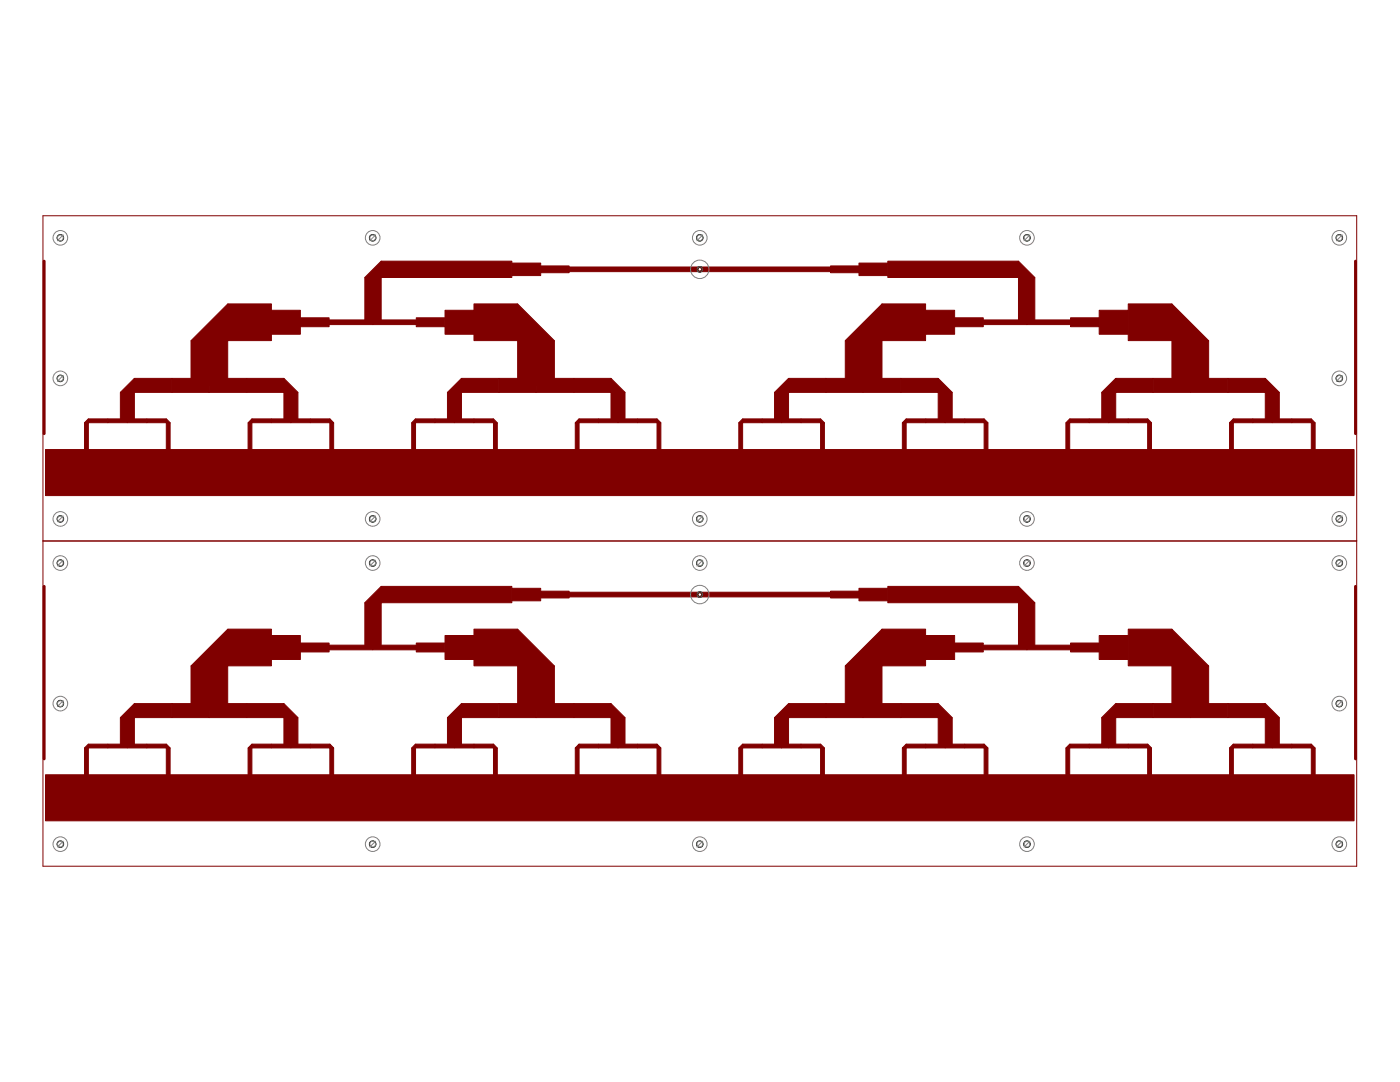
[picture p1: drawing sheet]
<svg xmlns="http://www.w3.org/2000/svg" width="279mm" height="216mm" viewBox="0 0 279 216" stroke-linecap="round" stroke-linejoin="round" font-family="sans-serif">
<circle cx="139.7" cy="118.6" r=".55" fill="#008000" stroke="#008000" stroke-width=".2"/>
<circle cx="139.7" cy="118.6" r=".36" fill="#fff" stroke="#000" stroke-width=".2"/>
<circle cx="139.7" cy="53.7" r=".55" fill="#008000" stroke="#008000" stroke-width=".2"/>
<circle cx="139.7" cy="53.7" r=".36" fill="#fff" stroke="#000" stroke-width=".2"/>
<g fill="#800000" stroke="#800000" stroke-width=".2">
<path d="M113.6 118.2h26.1v.9h-26.1z"/>
<path d="M139.7 118.2h26v.9h-26z"/>
<path d="M107.9 118h5.7v1.3h-5.7z"/>
<path d="M165.8 118h5.6v1.3h-5.6z"/>
<path d="M102.1 117.4h5.8v2.5h-5.8z"/>
<path d="M171.4 117.4h5.8v2.5h-5.8z"/>
<path d="M76.1 117h26v3.3h-26z"/>
<path d="M177.2 117h26.1v3.3h-26.1z"/>
<path d="M72.8 120.3l3.3-3.3 1.6 1.6-3.3 3.3z"/>
<path d="M203.3 117l3.2 3.3-1.6 1.6-3.3-3.3z"/>
<path d="M72.8 120.3h3.3v8.9h-3.3z"/>
<path d="M203.3 120.3h3.2v8.9h-3.2z"/>
<path d="M65.7 128.7h8.7v1h-8.7z"/>
<path d="M74.4 128.7h8.7v1h-8.7z"/>
<path d="M60 128.3h5.7v1.8h-5.7z"/>
<path d="M83.1 128.3h5.7v1.8h-5.7z"/>
<path d="M54.1 126.8h5.8v4.8h-5.8z"/>
<path d="M88.8 126.8h5.8v4.8h-5.8z"/>
<path d="M45.4 125.5h8.8v7.4h-8.8z"/>
<path d="M94.6 125.5h8.7v7.4h-8.7z"/>
<path d="M38.1 132.9l7.3-7.3 3.7 3.6-7.3 7.3z"/>
<path d="M230.2 129.2l3.7-3.6 7.3 7.3-3.7 3.6z"/>
<path d="M38.1 132.9h7.3v8.9h-7.3z"/>
<path d="M103.3 132.9h7.3v8.9h-7.3z"/>
<path d="M196.2 128.7h8.8v1h-8.8z"/>
<path d="M204.9 128.7h8.8v1h-8.8z"/>
<path d="M190.5 128.3h5.7v1.8h-5.7z"/>
<path d="M213.7 128.3h5.7v1.8h-5.7z"/>
<path d="M184.7 126.8h5.8v4.8h-5.8z"/>
<path d="M219.4 126.8h5.8v4.8h-5.8z"/>
<path d="M176 125.5h8.7v7.4h-8.7z"/>
<path d="M225.2 125.5h8.7v7.4h-8.7z"/>
<path d="M168.7 132.9l7.3-7.3 3.7 3.6-7.3 7.3z"/>
<path d="M99.7 129.2l3.6-3.6 7.3 7.3-3.6 3.6z"/>
<path d="M168.7 132.9h7.3v8.9h-7.3z"/>
<path d="M233.9 132.9h7.3v8.9h-7.3z"/>
<path d="M34.3 140.4h7.4v2.8h-7.4z"/>
<path d="M41.7 140.4h7.5v2.8h-7.5z"/>
<path d="M26.8 140.4h7.5v2.8h-7.5z"/>
<path d="M49.2 140.4h7.5v2.8h-7.5z"/>
<path d="M24 143.2l2.8-2.8 1.4 1.4-2.8 2.8z"/>
<path d="M251.1 141.8l1.4-1.4 2.8 2.8-1.4 1.4z"/>
<path d="M24 143.2h2.8v5.7h-2.8z"/>
<path d="M56.7 143.2h2.8v5.7h-2.8z"/>
<path d="M99.6 140.4h7.4v2.8h-7.4z"/>
<path d="M107 140.4h7.5v2.8h-7.5z"/>
<path d="M92.1 140.4h7.4v2.8h-7.4z"/>
<path d="M114.5 140.4h7.4v2.8h-7.4z"/>
<path d="M89.3 143.2l2.8-2.8 1.4 1.4-2.8 2.8z"/>
<path d="M185.8 141.8l1.4-1.4 2.8 2.8-1.4 1.4z"/>
<path d="M89.3 143.2h2.8v5.7h-2.8z"/>
<path d="M121.9 143.2h2.8v5.7h-2.8z"/>
<path d="M164.8 140.4h7.5v2.8h-7.5z"/>
<path d="M172.3 140.4h7.5v2.8h-7.5z"/>
<path d="M157.4 140.4h7.4v2.8h-7.4z"/>
<path d="M179.8 140.4h7.4v2.8h-7.4z"/>
<path d="M154.6 143.2l2.8-2.8 1.4 1.4-2.8 2.8z"/>
<path d="M120.5 141.8l1.4-1.4 2.8 2.8-1.4 1.4z"/>
<path d="M154.6 143.2h2.8v5.7h-2.8z"/>
<path d="M187.2 143.2h2.8v5.7h-2.8z"/>
<path d="M230.1 140.4h7.5v2.8h-7.5z"/>
<path d="M237.6 140.4h7.4v2.8h-7.4z"/>
<path d="M222.7 140.4h7.4v2.8h-7.4z"/>
<path d="M245.1 140.4h7.4v2.8h-7.4z"/>
<path d="M219.9 143.2l2.8-2.8 1.4 1.4-2.8 2.8z"/>
<path d="M55.3 141.8l1.4-1.4 2.8 2.8-1.4 1.4z"/>
<path d="M219.9 143.2h2.8v5.7h-2.8z"/>
<path d="M252.5 143.2h2.8v5.7h-2.8z"/>
<path d="M21.5 148.5h3.9v.7h-3.9z"/>
<path d="M25.4 148.5h3.9v.7h-3.9z"/>
<path d="M17.6 148.5h3.9v.7h-3.9z"/>
<path d="M29.3 148.5h3.9v.7h-3.9z"/>
<path d="M17.6 148.5l.4 .4-.7 .7-.4-.4z"/>
<path d="M261.3 148.9l.4-.4 .7 .7-.3 .4z"/>
<path d="M16.9 149.2h.7v5.4h-.7z"/>
<path d="M33.2 149.2h.8v5.4h-.8z"/>
<path d="M54.2 148.5h3.9v.7h-3.9z"/>
<path d="M58.1 148.5h3.9v.7h-3.9z"/>
<path d="M50.3 148.5h3.9v.7h-3.9z"/>
<path d="M62 148.5h3.8v.7h-3.8z"/>
<path d="M50.3 148.5l.4 .4-.8 .7-.4-.4z"/>
<path d="M228.7 148.9l.4-.4 .7 .7-.4 .4z"/>
<path d="M49.5 149.2h.8v5.4h-.8z"/>
<path d="M65.8 149.2h.8v5.4h-.8z"/>
<path d="M86.8 148.5h3.9v.7h-3.9z"/>
<path d="M90.7 148.5h3.9v.7h-3.9z"/>
<path d="M82.9 148.5h3.9v.7h-3.9z"/>
<path d="M94.6 148.5h3.9v.7h-3.9z"/>
<path d="M82.9 148.5l.4 .4-.8 .7-.3-.4z"/>
<path d="M196.4 148.5l.8 .7-.4 .4-.8-.7z"/>
<path d="M82.2 149.2h.7v5.4h-.7z"/>
<path d="M98.5 149.2h.7v5.4h-.7z"/>
<path d="M119.4 148.5h3.9v.7h-3.9z"/>
<path d="M123.3 148.5h3.9v.7h-3.9z"/>
<path d="M115.5 148.5h3.9v.7h-3.9z"/>
<path d="M127.2 148.5h3.9v.7h-3.9z"/>
<path d="M115.5 148.5l.4 .4-.7 .7-.4-.4z"/>
<path d="M163.8 148.5l.7 .7-.4 .4-.7-.7z"/>
<path d="M114.8 149.2h.8v5.4h-.8z"/>
<path d="M131.1 149.2h.8v5.4h-.8z"/>
<path d="M152.1 148.5h3.9v.7h-3.9z"/>
<path d="M156 148.5h3.9v.7h-3.9z"/>
<path d="M148.2 148.5h3.9v.7h-3.9z"/>
<path d="M159.9 148.5h3.9v.7h-3.9z"/>
<path d="M147.4 149.2l.8-.7 .4 .4-.8 .7z"/>
<path d="M130.7 148.9l.4-.4 .8 .7-.4 .4z"/>
<path d="M147.4 149.2h.8v5.4h-.8z"/>
<path d="M163.8 149.2h.7v5.4h-.7z"/>
<path d="M184.7 148.5h3.9v.7h-3.9z"/>
<path d="M188.6 148.5h3.9v.7h-3.9z"/>
<path d="M180.8 148.5h3.9v.7h-3.9z"/>
<path d="M192.5 148.5h3.9v.7h-3.9z"/>
<path d="M180.1 149.2l.7-.7 .4 .4-.7 .7z"/>
<path d="M98.5 148.5l.7 .7-.3 .4-.8-.7z"/>
<path d="M180.1 149.2h.7v5.4h-.7z"/>
<path d="M196.4 149.2h.8v5.4h-.8z"/>
<path d="M217.4 148.5h3.9v.7h-3.9z"/>
<path d="M221.3 148.5h3.9v.7h-3.9z"/>
<path d="M213.5 148.5h3.9v.7h-3.9z"/>
<path d="M225.2 148.5h3.9v.7h-3.9z"/>
<path d="M213.5 148.5l.4 .4-.8 .7-.4-.4z"/>
<path d="M65.5 148.9l.3-.4 .8 .7-.4 .4z"/>
<path d="M212.7 149.2h.8v5.4h-.8z"/>
<path d="M229 149.2h.8v5.4h-.8z"/>
<path d="M250 148.5h3.9v.7h-3.9z"/>
<path d="M253.9 148.5h3.9v.7h-3.9z"/>
<path d="M246.1 148.5h3.9v.7h-3.9z"/>
<path d="M257.8 148.5h3.9v.7h-3.9z"/>
<path d="M246.1 148.5l.4 .4-.7 .7-.4-.4z"/>
<path d="M32.8 148.9l.4-.4 .8 .7-.4 .4z"/>
<path d="M245.4 149.2h.7v5.4h-.7z"/>
<path d="M261.7 149.2h.8v5.4h-.8z"/>
<path d="M9.1 154.6h261.1v9.2h-261.1z"/>
<path d="M113.6 53.3h26.1v.9h-26.1z"/>
<path d="M139.7 53.3h26v.9h-26z"/>
<path d="M107.9 53.1h5.7v1.3h-5.7z"/>
<path d="M165.8 53.1h5.6v1.3h-5.6z"/>
<path d="M102.1 52.5h5.8v2.5h-5.8z"/>
<path d="M171.4 52.5h5.8v2.5h-5.8z"/>
<path d="M76.1 52.1h26v3.3h-26z"/>
<path d="M177.2 52.1h26.1v3.3h-26.1z"/>
<path d="M72.8 55.4l3.3-3.3 1.6 1.6-3.3 3.3z"/>
<path d="M203.3 52.1l3.2 3.3-1.6 1.6-3.3-3.3z"/>
<path d="M72.8 55.4h3.3v8.9h-3.3z"/>
<path d="M203.3 55.4h3.2v8.9h-3.2z"/>
<path d="M65.7 63.8h8.7v1h-8.7z"/>
<path d="M74.4 63.8h8.7v1h-8.7z"/>
<path d="M60 63.4h5.7v1.8h-5.7z"/>
<path d="M83.1 63.4h5.7v1.8h-5.7z"/>
<path d="M54.1 61.9h5.8v4.8h-5.8z"/>
<path d="M88.8 61.9h5.8v4.8h-5.8z"/>
<path d="M45.4 60.6h8.8v7.4h-8.8z"/>
<path d="M94.6 60.6h8.7v7.4h-8.7z"/>
<path d="M38.1 68l7.3-7.3 3.7 3.6-7.3 7.3z"/>
<path d="M230.2 64.3l3.7-3.6 7.3 7.3-3.7 3.6z"/>
<path d="M38.1 68h7.3v8.9h-7.3z"/>
<path d="M103.3 68h7.3v8.9h-7.3z"/>
<path d="M196.2 63.8h8.8v1h-8.8z"/>
<path d="M204.9 63.8h8.8v1h-8.8z"/>
<path d="M190.5 63.4h5.7v1.8h-5.7z"/>
<path d="M213.7 63.4h5.7v1.8h-5.7z"/>
<path d="M184.7 61.9h5.8v4.8h-5.8z"/>
<path d="M219.4 61.9h5.8v4.8h-5.8z"/>
<path d="M176 60.6h8.7v7.4h-8.7z"/>
<path d="M225.2 60.6h8.7v7.4h-8.7z"/>
<path d="M168.7 68l7.3-7.3 3.7 3.6-7.3 7.3z"/>
<path d="M99.7 64.3l3.6-3.6 7.3 7.3-3.6 3.6z"/>
<path d="M168.7 68h7.3v8.9h-7.3z"/>
<path d="M233.9 68h7.3v8.9h-7.3z"/>
<path d="M34.3 75.5h7.4v2.8h-7.4z"/>
<path d="M41.7 75.5h7.5v2.8h-7.5z"/>
<path d="M26.8 75.5h7.5v2.8h-7.5z"/>
<path d="M49.2 75.5h7.5v2.8h-7.5z"/>
<path d="M24 78.3l2.8-2.8 1.4 1.4-2.8 2.8z"/>
<path d="M251.1 76.9l1.4-1.4 2.8 2.8-1.4 1.4z"/>
<path d="M24 78.3h2.8v5.7h-2.8z"/>
<path d="M56.7 78.3h2.8v5.7h-2.8z"/>
<path d="M99.6 75.5h7.4v2.8h-7.4z"/>
<path d="M107 75.5h7.5v2.8h-7.5z"/>
<path d="M92.1 75.5h7.4v2.8h-7.4z"/>
<path d="M114.5 75.5h7.4v2.8h-7.4z"/>
<path d="M89.3 78.3l2.8-2.8 1.4 1.4-2.8 2.8z"/>
<path d="M185.8 76.9l1.4-1.4 2.8 2.8-1.4 1.4z"/>
<path d="M89.3 78.3h2.8v5.7h-2.8z"/>
<path d="M121.9 78.3h2.8v5.7h-2.8z"/>
<path d="M164.8 75.5h7.5v2.8h-7.5z"/>
<path d="M172.3 75.5h7.5v2.8h-7.5z"/>
<path d="M157.4 75.5h7.4v2.8h-7.4z"/>
<path d="M179.8 75.5h7.4v2.8h-7.4z"/>
<path d="M154.6 78.3l2.8-2.8 1.4 1.4-2.8 2.8z"/>
<path d="M120.5 76.9l1.4-1.4 2.8 2.8-1.4 1.4z"/>
<path d="M154.6 78.3h2.8v5.7h-2.8z"/>
<path d="M187.2 78.3h2.8v5.7h-2.8z"/>
<path d="M230.1 75.5h7.5v2.8h-7.5z"/>
<path d="M237.6 75.5h7.4v2.8h-7.4z"/>
<path d="M222.7 75.5h7.4v2.8h-7.4z"/>
<path d="M245.1 75.5h7.4v2.8h-7.4z"/>
<path d="M219.9 78.3l2.8-2.8 1.4 1.4-2.8 2.8z"/>
<path d="M55.3 76.9l1.4-1.4 2.8 2.8-1.4 1.4z"/>
<path d="M219.9 78.3h2.8v5.7h-2.8z"/>
<path d="M252.5 78.3h2.8v5.7h-2.8z"/>
<path d="M21.5 83.6h3.9v.7h-3.9z"/>
<path d="M25.4 83.6h3.9v.7h-3.9z"/>
<path d="M17.6 83.6h3.9v.7h-3.9z"/>
<path d="M29.3 83.6h3.9v.7h-3.9z"/>
<path d="M16.9 84.3l.7-.7 .4 .4-.7 .7z"/>
<path d="M261.3 84l.4-.4 .7 .7-.3 .4z"/>
<path d="M16.9 84.3h.7v5.4h-.7z"/>
<path d="M33.2 84.3h.8v5.4h-.8z"/>
<path d="M54.2 83.6h3.9v.7h-3.9z"/>
<path d="M58.1 83.6h3.9v.7h-3.9z"/>
<path d="M50.3 83.6h3.9v.7h-3.9z"/>
<path d="M62 83.6h3.8v.7h-3.8z"/>
<path d="M50.3 83.6l.4 .4-.8 .7-.4-.4z"/>
<path d="M228.7 84l.4-.4 .7 .7-.4 .4z"/>
<path d="M49.5 84.3h.8v5.4h-.8z"/>
<path d="M65.8 84.3h.8v5.4h-.8z"/>
<path d="M86.8 83.6h3.9v.7h-3.9z"/>
<path d="M90.7 83.6h3.9v.7h-3.9z"/>
<path d="M82.9 83.6h3.9v.7h-3.9z"/>
<path d="M94.6 83.6h3.9v.7h-3.9z"/>
<path d="M82.9 83.6l.4 .4-.8 .7-.3-.4z"/>
<path d="M196.4 83.6l.8 .7-.4 .4-.8-.7z"/>
<path d="M82.2 84.3h.7v5.4h-.7z"/>
<path d="M98.5 84.3h.7v5.4h-.7z"/>
<path d="M119.4 83.6h3.9v.7h-3.9z"/>
<path d="M123.3 83.6h3.9v.7h-3.9z"/>
<path d="M115.5 83.6h3.9v.7h-3.9z"/>
<path d="M127.2 83.6h3.9v.7h-3.9z"/>
<path d="M115.5 83.6l.4 .4-.7 .7-.4-.4z"/>
<path d="M163.8 83.6l.7 .7-.4 .4-.7-.7z"/>
<path d="M114.8 84.3h.8v5.4h-.8z"/>
<path d="M131.1 84.3h.8v5.4h-.8z"/>
<path d="M152.1 83.6h3.9v.7h-3.9z"/>
<path d="M156 83.6h3.9v.7h-3.9z"/>
<path d="M148.2 83.6h3.9v.7h-3.9z"/>
<path d="M159.9 83.6h3.9v.7h-3.9z"/>
<path d="M147.4 84.3l.8-.7 .4 .4-.8 .7z"/>
<path d="M130.7 84l.4-.4 .8 .7-.4 .4z"/>
<path d="M147.4 84.3h.8v5.4h-.8z"/>
<path d="M163.8 84.3h.7v5.4h-.7z"/>
<path d="M184.7 83.6h3.9v.7h-3.9z"/>
<path d="M188.6 83.6h3.9v.7h-3.9z"/>
<path d="M180.8 83.6h3.9v.7h-3.9z"/>
<path d="M192.5 83.6h3.9v.7h-3.9z"/>
<path d="M180.1 84.3l.7-.7 .4 .4-.7 .7z"/>
<path d="M98.5 83.6l.7 .7-.3 .4-.8-.7z"/>
<path d="M180.1 84.3h.7v5.4h-.7z"/>
<path d="M196.4 84.3h.8v5.4h-.8z"/>
<path d="M217.4 83.6h3.9v.7h-3.9z"/>
<path d="M221.3 83.6h3.9v.7h-3.9z"/>
<path d="M213.5 83.6h3.9v.7h-3.9z"/>
<path d="M225.2 83.6h3.9v.7h-3.9z"/>
<path d="M213.5 83.6l.4 .4-.8 .7-.4-.4z"/>
<path d="M65.5 84l.3-.4 .8 .7-.4 .4z"/>
<path d="M212.7 84.3h.8v5.4h-.8z"/>
<path d="M229 84.3h.8v5.4h-.8z"/>
<path d="M250 83.6h3.9v.7h-3.9z"/>
<path d="M253.9 83.6h3.9v.7h-3.9z"/>
<path d="M246.1 83.6h3.9v.7h-3.9z"/>
<path d="M257.8 83.6h3.9v.7h-3.9z"/>
<path d="M246.1 83.6l.4 .4-.7 .7-.4-.4z"/>
<path d="M32.8 84l.4-.4 .8 .7-.4 .4z"/>
<path d="M245.4 84.3h.7v5.4h-.7z"/>
<path d="M261.7 84.3h.8v5.4h-.8z"/>
<path d="M9.1 89.7h261.1v9.2h-261.1z"/>
</g>
<g fill="#800000" stroke="#800000" stroke-width=".59">
<path d="M270.5 117v34.4z"/>
<path d="M8.8 117v34.4z"/>
<path d="M270.5 52.1v34.4z"/>
<path d="M8.8 52.1v34.4z"/>
</g>
<g fill="#800000" stroke="#800000" stroke-width=".2">
<path d="M8.6 107.9h262.2z"/>
<path d="M8.6 107.9v64.9z"/>
<path d="M8.6 172.8h262.2z"/>
<path d="M270.8 107.9v64.9z"/>
<path d="M8.6 43.1h262.2z"/>
<path d="M8.6 43.1v64.8z"/>
<path d="M270.8 43.1v64.8z"/>
</g>
<circle cx="139.7" cy="118.6" r=".55" fill="#008000" stroke="#008000" stroke-width=".2"/>
<circle cx="139.7" cy="118.6" r=".36" fill="#fff" stroke="#000" stroke-width=".2"/>
<circle cx="139.7" cy="53.7" r=".55" fill="#008000" stroke="#008000" stroke-width=".2"/>
<circle cx="139.7" cy="53.7" r=".36" fill="#fff" stroke="#000" stroke-width=".2"/>
<g fill="none" stroke="#808080" stroke-width=".2">
<circle cx="12" cy="47.5" r="1.46"/>
<circle cx="12" cy="47.5" r=".57"/>
<circle cx="74.4" cy="47.5" r="1.46"/>
<circle cx="74.4" cy="47.5" r=".57"/>
<circle cx="139.7" cy="53.7" r="1.84"/>
<circle cx="139.7" cy="47.5" r="1.46"/>
<circle cx="139.7" cy="47.5" r=".57"/>
<circle cx="205" cy="47.5" r="1.46"/>
<circle cx="205" cy="47.5" r=".57"/>
<circle cx="267.3" cy="47.5" r="1.46"/>
<circle cx="267.3" cy="47.5" r=".57"/>
<circle cx="12" cy="75.5" r="1.46"/>
<circle cx="12" cy="75.5" r=".57"/>
<circle cx="267.3" cy="75.5" r="1.46"/>
<circle cx="267.3" cy="75.5" r=".57"/>
<circle cx="12" cy="112.4" r="1.46"/>
<circle cx="12" cy="103.5" r="1.46"/>
<circle cx="12" cy="112.4" r=".57"/>
<circle cx="12" cy="103.5" r=".57"/>
<circle cx="74.4" cy="112.4" r="1.46"/>
<circle cx="74.4" cy="103.5" r="1.46"/>
<circle cx="74.4" cy="112.4" r=".57"/>
<circle cx="74.4" cy="103.5" r=".57"/>
<circle cx="139.7" cy="118.6" r="1.84"/>
<circle cx="139.7" cy="112.4" r="1.46"/>
<circle cx="139.7" cy="103.5" r="1.46"/>
<circle cx="139.7" cy="112.4" r=".57"/>
<circle cx="139.7" cy="103.5" r=".57"/>
<circle cx="205" cy="112.4" r="1.46"/>
<circle cx="205" cy="103.5" r="1.46"/>
<circle cx="205" cy="112.4" r=".57"/>
<circle cx="205" cy="103.5" r=".57"/>
<circle cx="267.3" cy="112.4" r="1.46"/>
<circle cx="267.3" cy="103.5" r="1.46"/>
<circle cx="267.3" cy="112.4" r=".57"/>
<circle cx="267.3" cy="103.5" r=".57"/>
<circle cx="12" cy="140.4" r="1.46"/>
<circle cx="12" cy="140.4" r=".57"/>
<circle cx="267.3" cy="140.4" r="1.46"/>
<circle cx="267.3" cy="140.4" r=".57"/>
<circle cx="12" cy="168.4" r="1.46"/>
<circle cx="12" cy="168.4" r=".57"/>
<circle cx="74.4" cy="168.4" r="1.46"/>
<circle cx="74.4" cy="168.4" r=".57"/>
<circle cx="139.7" cy="168.4" r="1.46"/>
<circle cx="139.7" cy="168.4" r=".57"/>
<circle cx="205" cy="168.4" r="1.46"/>
<circle cx="205" cy="168.4" r=".57"/>
<circle cx="267.3" cy="168.4" r="1.46"/>
<circle cx="267.3" cy="168.4" r=".57"/>
</g>
<g fill="none" stroke="#000" stroke-width=".2">
<circle cx="12" cy="47.5" r=".66"/>
<circle cx="74.4" cy="47.5" r=".66"/>
<circle cx="139.7" cy="47.5" r=".66"/>
<circle cx="205" cy="47.5" r=".66"/>
<circle cx="267.3" cy="47.5" r=".66"/>
<circle cx="12" cy="75.5" r=".66"/>
<circle cx="267.3" cy="75.5" r=".66"/>
<circle cx="12" cy="112.4" r=".66"/>
<circle cx="12" cy="103.5" r=".66"/>
<circle cx="74.4" cy="112.4" r=".66"/>
<circle cx="74.4" cy="103.5" r=".66"/>
<circle cx="139.7" cy="112.4" r=".66"/>
<circle cx="139.7" cy="103.5" r=".66"/>
<circle cx="205" cy="112.4" r=".66"/>
<circle cx="205" cy="103.5" r=".66"/>
<circle cx="267.3" cy="112.4" r=".66"/>
<circle cx="267.3" cy="103.5" r=".66"/>
<circle cx="12" cy="140.4" r=".66"/>
<circle cx="267.3" cy="140.4" r=".66"/>
<circle cx="12" cy="168.4" r=".66"/>
<circle cx="74.4" cy="168.4" r=".66"/>
<circle cx="139.7" cy="168.4" r=".66"/>
<circle cx="205" cy="168.4" r=".66"/>
<circle cx="267.3" cy="168.4" r=".66"/>
</g>
<g fill="#808080" stroke="#808080" stroke-width=".2">
<path d="M11.5 112.9l1.1-1.1z"/>
<path d="M12.6 139.8l-1.1 1.2z"/>
<path d="M11.5 169l1.1-1.2z"/>
<path d="M73.8 112.9l1.2-1.1z"/>
<path d="M73.8 169l1.2-1.2z"/>
<path d="M139.1 112.9l1.1-1.1z"/>
<path d="M139.1 169l1.1-1.2z"/>
<path d="M204.4 112.9l1.1-1.1z"/>
<path d="M204.4 169l1.1-1.2z"/>
<path d="M266.7 112.9l1.2-1.1z"/>
<path d="M266.7 141l1.2-1.2z"/>
<path d="M266.7 169l1.2-1.2z"/>
<path d="M12.6 46.9l-1.1 1.1z"/>
<path d="M12.6 74.9l-1.1 1.2z"/>
<path d="M11.5 104.1l1.1-1.1z"/>
<path d="M73.8 48l1.2-1.1z"/>
<path d="M73.8 104.1l1.2-1.1z"/>
<path d="M140.2 46.9l-1.1 1.1z"/>
<path d="M139.1 104.1l1.1-1.1z"/>
<path d="M204.4 48l1.1-1.1z"/>
<path d="M204.4 104.1l1.1-1.1z"/>
<path d="M266.7 48l1.2-1.1z"/>
<path d="M266.7 76.1l1.2-1.2z"/>
<path d="M266.7 104.1l1.2-1.1z"/>
</g>
</svg>
